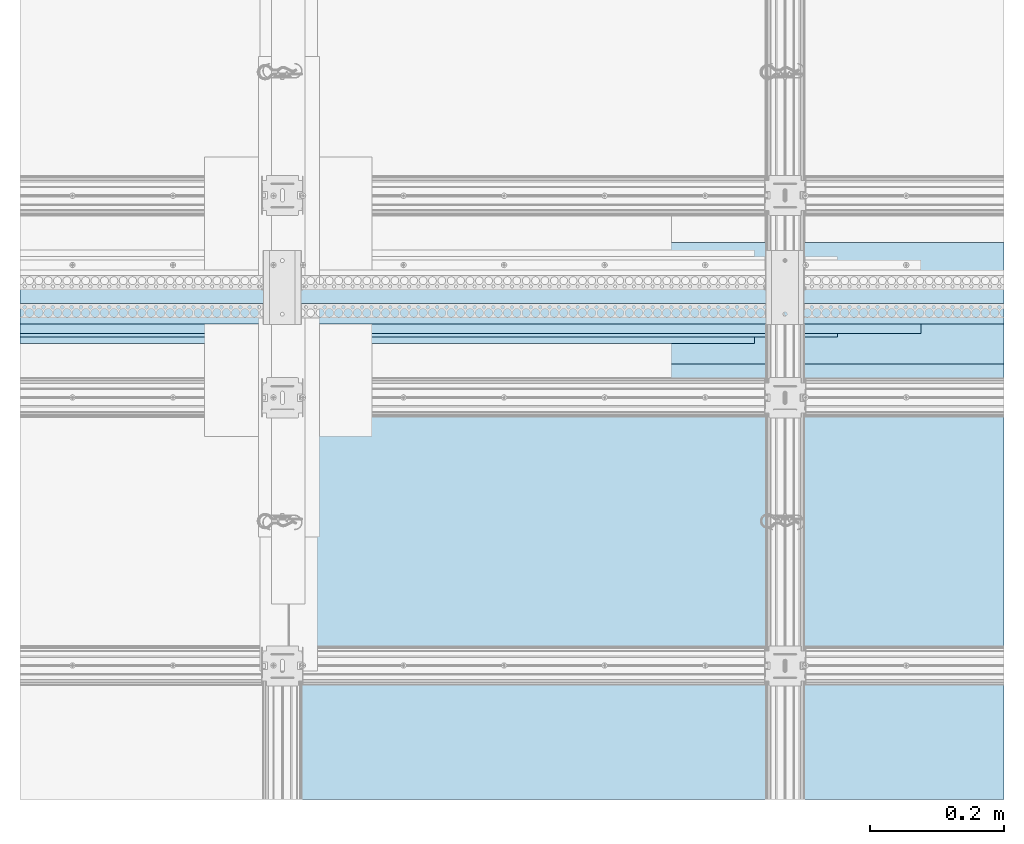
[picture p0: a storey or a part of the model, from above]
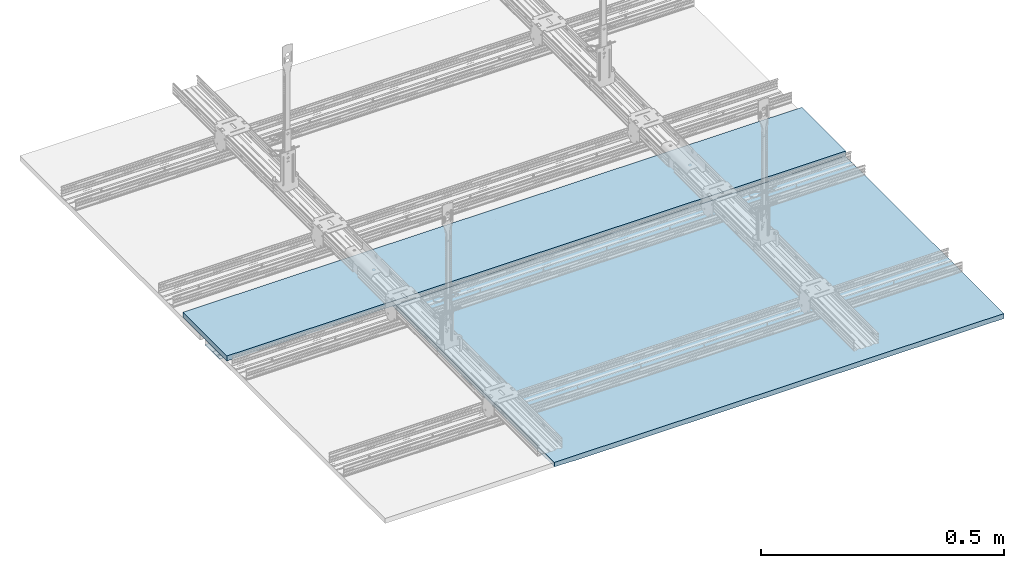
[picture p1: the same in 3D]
Properties of the parts of a building model (IFC2X3)

# File
Description: ViewDefinition [CoordinationView]
Time: 2022-02-01T09:51:14
Made in: SketchUp Pro 2015

# IfcProject, Default Project
Description: Description of Default Project

# IfcSite, Default Site
Description: Description of Default Site; RefLatitude: 24, 28, 0; RefLongitude: 54, 25, 0; RefElevation: 10 mm

# IfcBuilding, Default Building
Description: Description of Default Building

# IfcBuildingStorey, Default Building Storey
In: Default Building
Description: Description of Default Building Storey; Elevation: 0 mm

# IfcSlab (109)
In: Default Building Storey
Description: Description of Object
PredefinedType - IfcSlabTypeEnum: floor
Name
5 x Płyta gipsowo-kartonowa RIGIPS PRO (4PRO™)
4 x Dedykowana masa szpachlowa Rigips - wykończeniowa
4 x Taśma spoinowa RIGIPS
10 x Dedykowana masa szpachlowa Rigips - konstrukcyjna
2 x Półnarożnik aluminiowy
4 x Część górna wieszaka noniuszowego
8 x Łącznik krzyżowy RIGIPS do profilu CD 60
50 x Wkręt RIGIPS TN 25
8 x Klamra zabezpieczająca do wieszaków noniuszowych
8 x Profil RIGIPS CD 60 ULTRASTIL®
4 x Wieszak obrotowy RIGIPS noniuszowy
2 x Łącznik wzdłużny do profilu CD 60
